VERSION 5.7 ;
  NOWIREEXTENSIONATPIN ON ;
  DIVIDERCHAR "/" ;
  BUSBITCHARS "[]" ;
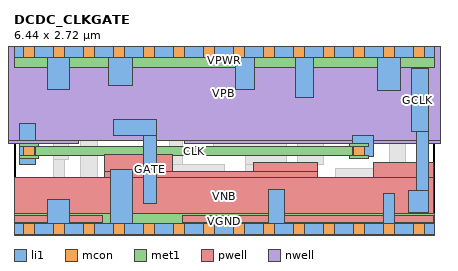
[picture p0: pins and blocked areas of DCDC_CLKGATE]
MACRO DCDC_CLKGATE
  CLASS BLOCK ;
  FOREIGN DCDC_CLKGATE ;
  ORIGIN -0.190 -0.240 ;
  SIZE 6.440 BY 2.720 ;
  PIN GATE
    ANTENNAGATEAREA 0.159000 ;
    PORT
      LAYER li1 ;
        RECT 1.715 1.675 2.375 1.925 ;
        RECT 2.175 0.625 2.375 1.675 ;
    END
  END GATE
  PIN GCLK
    ANTENNADIFFAREA 0.429000 ;
    PORT
      LAYER li1 ;
        RECT 6.280 1.735 6.545 2.695 ;
        RECT 6.360 0.835 6.545 1.735 ;
        RECT 6.245 0.495 6.545 0.835 ;
    END
  END GCLK
  PIN CLK
    ANTENNAGATEAREA 0.318000 ;
    PORT
      LAYER li1 ;
        RECT 0.275 1.225 0.520 1.865 ;
        RECT 5.380 1.345 5.700 1.675 ;
      LAYER mcon ;
        RECT 0.335 1.345 0.505 1.515 ;
        RECT 5.400 1.345 5.570 1.515 ;
      LAYER met1 ;
        RECT 0.275 1.500 0.570 1.545 ;
        RECT 5.340 1.500 5.630 1.545 ;
        RECT 0.275 1.360 5.630 1.500 ;
        RECT 0.275 1.315 0.570 1.360 ;
        RECT 5.340 1.315 5.630 1.360 ;
    END
  END CLK
  PIN VNB
    PORT
      LAYER pwell ;
        RECT 1.585 1.120 2.625 1.385 ;
        RECT 3.865 1.120 4.850 1.255 ;
        RECT 1.585 1.025 4.850 1.120 ;
        RECT 5.705 1.025 6.625 1.255 ;
        RECT 0.195 0.440 6.625 1.025 ;
        RECT 0.195 0.345 1.545 0.440 ;
        RECT 2.770 0.345 6.625 0.440 ;
        RECT 0.340 0.155 0.510 0.345 ;
    END
  END VNB
  PIN VPB
    PORT
      LAYER nwell ;
        RECT 0.000 1.595 6.820 3.150 ;
        RECT 0.000 1.545 1.185 1.595 ;
        RECT 2.810 1.545 6.820 1.595 ;
    END
  END VPB
  PIN VGND
    USE GROUND ;
    PORT
      LAYER li1 ;
        RECT 0.705 0.325 1.035 0.685 ;
        RECT 1.670 0.325 2.000 1.145 ;
        RECT 4.085 0.325 4.335 0.850 ;
        RECT 5.860 0.325 6.030 0.785 ;
        RECT 0.190 0.155 6.630 0.325 ;
      LAYER mcon ;
        RECT 0.335 0.155 0.505 0.325 ;
        RECT 0.795 0.155 0.965 0.325 ;
        RECT 1.255 0.155 1.425 0.325 ;
        RECT 1.715 0.155 1.885 0.325 ;
        RECT 2.175 0.155 2.345 0.325 ;
        RECT 2.635 0.155 2.805 0.325 ;
        RECT 3.095 0.155 3.265 0.325 ;
        RECT 3.555 0.155 3.725 0.325 ;
        RECT 4.015 0.155 4.185 0.325 ;
        RECT 4.475 0.155 4.645 0.325 ;
        RECT 4.935 0.155 5.105 0.325 ;
        RECT 5.395 0.155 5.565 0.325 ;
        RECT 5.855 0.155 6.025 0.325 ;
        RECT 6.315 0.155 6.485 0.325 ;
      LAYER met1 ;
        RECT 0.190 0.000 6.630 0.480 ;
    END
  END VGND
  PIN VPWR
    USE POWER ;
    PORT
      LAYER li1 ;
        RECT 0.190 2.875 6.630 3.045 ;
        RECT 0.705 2.375 1.035 2.875 ;
        RECT 1.640 2.435 2.005 2.875 ;
        RECT 3.585 2.375 3.885 2.875 ;
        RECT 4.500 2.250 4.785 2.875 ;
        RECT 5.760 2.370 6.110 2.875 ;
      LAYER mcon ;
        RECT 0.335 2.875 0.505 3.045 ;
        RECT 0.795 2.875 0.965 3.045 ;
        RECT 1.255 2.875 1.425 3.045 ;
        RECT 1.715 2.875 1.885 3.045 ;
        RECT 2.175 2.875 2.345 3.045 ;
        RECT 2.635 2.875 2.805 3.045 ;
        RECT 3.095 2.875 3.265 3.045 ;
        RECT 3.555 2.875 3.725 3.045 ;
        RECT 4.015 2.875 4.185 3.045 ;
        RECT 4.475 2.875 4.645 3.045 ;
        RECT 4.935 2.875 5.105 3.045 ;
        RECT 5.395 2.875 5.565 3.045 ;
        RECT 5.855 2.875 6.025 3.045 ;
        RECT 6.315 2.875 6.485 3.045 ;
      LAYER met1 ;
        RECT 0.190 2.720 6.630 3.200 ;
    END
  END VPWR
  OBS
      LAYER li1 ;
        RECT 0.365 2.205 0.535 2.705 ;
        RECT 1.205 2.265 1.430 2.705 ;
        RECT 2.665 2.495 3.415 2.665 ;
        RECT 0.365 2.035 0.970 2.205 ;
        RECT 0.800 1.630 0.970 2.035 ;
        RECT 1.205 2.095 2.780 2.265 ;
        RECT 0.800 1.300 1.030 1.630 ;
        RECT 0.800 1.025 0.970 1.300 ;
        RECT 0.365 0.855 0.970 1.025 ;
        RECT 0.365 0.500 0.535 0.855 ;
        RECT 1.205 0.500 1.470 2.095 ;
        RECT 2.580 1.225 2.780 2.095 ;
        RECT 3.245 1.565 3.415 2.495 ;
        RECT 4.100 2.105 4.320 2.675 ;
        RECT 3.620 2.080 4.320 2.105 ;
        RECT 5.195 2.135 5.525 2.705 ;
        RECT 3.620 1.775 4.900 2.080 ;
        RECT 5.195 1.965 6.110 2.135 ;
        RECT 4.535 1.565 4.900 1.775 ;
        RECT 5.940 1.565 6.110 1.965 ;
        RECT 3.245 1.395 4.365 1.565 ;
        RECT 3.745 1.235 4.365 1.395 ;
        RECT 4.535 1.235 4.930 1.565 ;
        RECT 2.580 1.055 3.410 1.225 ;
        RECT 3.745 0.800 3.915 1.235 ;
        RECT 4.535 0.855 4.770 1.235 ;
        RECT 5.940 1.175 6.190 1.565 ;
        RECT 5.125 1.005 6.190 1.175 ;
        RECT 5.125 0.860 5.345 1.005 ;
        RECT 2.980 0.630 3.915 0.800 ;
        RECT 4.510 0.495 4.770 0.855 ;
        RECT 5.030 0.530 5.345 0.860 ;
  END
END DCDC_CLKGATE
END LIBRARY
